VERSION 5.7 ;
  NOWIREEXTENSIONATPIN ON ;
  DIVIDERCHAR "/" ;
  BUSBITCHARS "[]" ;
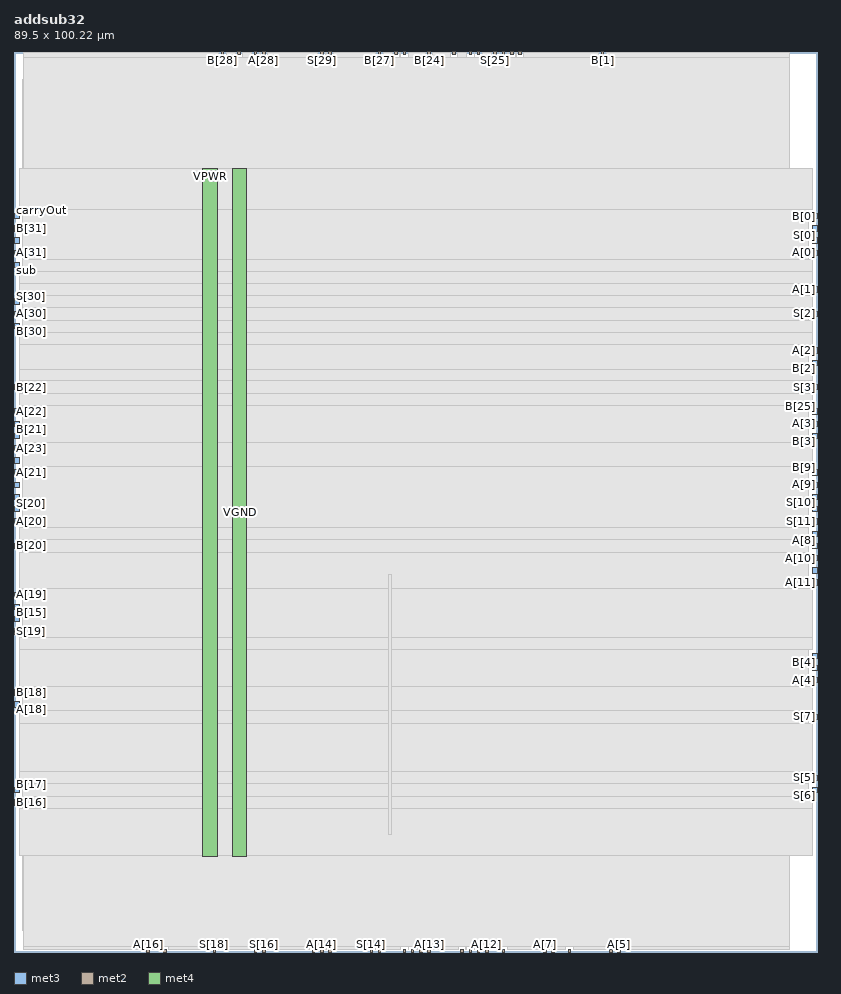
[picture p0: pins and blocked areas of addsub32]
MACRO addsub32
  CLASS BLOCK ;
  FOREIGN addsub32 ;
  ORIGIN 0.000 0.000 ;
  SIZE 89.500 BY 100.220 ;
  PIN A[0]
    DIRECTION INPUT ;
    USE SIGNAL ;
    ANTENNAGATEAREA 0.126000 ;
    PORT
      LAYER met3 ;
        RECT 88.900 77.560 89.500 78.160 ;
    END
  END A[0]
  PIN A[10]
    DIRECTION INPUT ;
    USE SIGNAL ;
    ANTENNAGATEAREA 0.213000 ;
    PORT
      LAYER met3 ;
        RECT 88.900 43.560 89.500 44.160 ;
    END
  END A[10]
  PIN A[11]
    DIRECTION INPUT ;
    USE SIGNAL ;
    ANTENNAGATEAREA 0.213000 ;
    PORT
      LAYER met3 ;
        RECT 88.900 40.840 89.500 41.440 ;
    END
  END A[11]
  PIN A[12]
    DIRECTION INPUT ;
    USE SIGNAL ;
    ANTENNAGATEAREA 0.213000 ;
    PORT
      LAYER met2 ;
        RECT 52.530 0.000 52.810 0.280 ;
    END
  END A[12]
  PIN A[13]
    DIRECTION INPUT ;
    USE SIGNAL ;
    ANTENNAGATEAREA 0.213000 ;
    PORT
      LAYER met2 ;
        RECT 46.090 0.000 46.370 0.280 ;
    END
  END A[13]
  PIN A[14]
    DIRECTION INPUT ;
    USE SIGNAL ;
    ANTENNAGATEAREA 0.213000 ;
    PORT
      LAYER met2 ;
        RECT 34.130 0.000 34.410 0.280 ;
    END
  END A[14]
  PIN A[15]
    DIRECTION INPUT ;
    USE SIGNAL ;
    ANTENNAGATEAREA 0.213000 ;
    PORT
      LAYER met2 ;
        RECT 35.050 0.000 35.330 0.280 ;
    END
  END A[15]
  PIN A[16]
    DIRECTION INPUT ;
    USE SIGNAL ;
    ANTENNAGATEAREA 0.213000 ;
    PORT
      LAYER met2 ;
        RECT 14.810 0.000 15.090 0.280 ;
    END
  END A[16]
  PIN A[17]
    DIRECTION INPUT ;
    USE SIGNAL ;
    ANTENNAGATEAREA 0.213000 ;
    PORT
      LAYER met2 ;
        RECT 16.650 0.000 16.930 0.280 ;
    END
  END A[17]
  PIN A[18]
    DIRECTION INPUT ;
    USE SIGNAL ;
    ANTENNAGATEAREA 0.213000 ;
    PORT
      LAYER met3 ;
        RECT 0.000 27.240 0.600 27.840 ;
    END
  END A[18]
  PIN A[19]
    DIRECTION INPUT ;
    USE SIGNAL ;
    ANTENNAGATEAREA 0.213000 ;
    PORT
      LAYER met3 ;
        RECT 0.000 39.480 0.600 40.080 ;
    END
  END A[19]
  PIN A[1]
    DIRECTION INPUT ;
    USE SIGNAL ;
    ANTENNAGATEAREA 0.126000 ;
    PORT
      LAYER met3 ;
        RECT 88.900 73.480 89.500 74.080 ;
    END
  END A[1]
  PIN A[20]
    DIRECTION INPUT ;
    USE SIGNAL ;
    ANTENNAGATEAREA 0.213000 ;
    PORT
      LAYER met3 ;
        RECT 0.000 47.640 0.600 48.240 ;
    END
  END A[20]
  PIN A[21]
    DIRECTION INPUT ;
    USE SIGNAL ;
    ANTENNAGATEAREA 0.213000 ;
    PORT
      LAYER met3 ;
        RECT 0.000 53.080 0.600 53.680 ;
    END
  END A[21]
  PIN A[22]
    DIRECTION INPUT ;
    USE SIGNAL ;
    ANTENNAGATEAREA 0.213000 ;
    PORT
      LAYER met3 ;
        RECT 0.000 59.880 0.600 60.480 ;
    END
  END A[22]
  PIN A[23]
    DIRECTION INPUT ;
    USE SIGNAL ;
    ANTENNAGATEAREA 0.213000 ;
    PORT
      LAYER met3 ;
        RECT 0.000 55.800 0.600 56.400 ;
    END
  END A[23]
  PIN A[24]
    DIRECTION INPUT ;
    USE SIGNAL ;
    ANTENNAGATEAREA 0.213000 ;
    PORT
      LAYER met2 ;
        RECT 48.850 99.940 49.130 100.220 ;
    END
  END A[24]
  PIN A[25]
    DIRECTION INPUT ;
    USE SIGNAL ;
    ANTENNAGATEAREA 0.213000 ;
    PORT
      LAYER met2 ;
        RECT 51.610 99.940 51.890 100.220 ;
    END
  END A[25]
  PIN A[26]
    DIRECTION INPUT ;
    USE SIGNAL ;
    ANTENNAGATEAREA 0.213000 ;
    PORT
      LAYER met2 ;
        RECT 56.210 99.940 56.490 100.220 ;
    END
  END A[26]
  PIN A[27]
    DIRECTION INPUT ;
    USE SIGNAL ;
    ANTENNAGATEAREA 0.213000 ;
    PORT
      LAYER met2 ;
        RECT 43.330 99.940 43.610 100.220 ;
    END
  END A[27]
  PIN A[28]
    DIRECTION INPUT ;
    USE SIGNAL ;
    ANTENNAGATEAREA 0.213000 ;
    PORT
      LAYER met2 ;
        RECT 27.690 99.940 27.970 100.220 ;
    END
  END A[28]
  PIN A[29]
    DIRECTION INPUT ;
    USE SIGNAL ;
    ANTENNAGATEAREA 0.213000 ;
    PORT
      LAYER met2 ;
        RECT 26.770 99.940 27.050 100.220 ;
    END
  END A[29]
  PIN A[2]
    DIRECTION INPUT ;
    USE SIGNAL ;
    ANTENNAGATEAREA 0.213000 ;
    PORT
      LAYER met3 ;
        RECT 88.900 66.680 89.500 67.280 ;
    END
  END A[2]
  PIN A[30]
    DIRECTION INPUT ;
    USE SIGNAL ;
    ANTENNAGATEAREA 0.213000 ;
    PORT
      LAYER met3 ;
        RECT 0.000 70.760 0.600 71.360 ;
    END
  END A[30]
  PIN A[31]
    DIRECTION INPUT ;
    USE SIGNAL ;
    ANTENNAGATEAREA 0.213000 ;
    PORT
      LAYER met3 ;
        RECT 0.000 77.560 0.600 78.160 ;
    END
  END A[31]
  PIN A[3]
    DIRECTION INPUT ;
    USE SIGNAL ;
    ANTENNAGATEAREA 0.213000 ;
    PORT
      LAYER met3 ;
        RECT 88.900 58.520 89.500 59.120 ;
    END
  END A[3]
  PIN A[4]
    DIRECTION INPUT ;
    USE SIGNAL ;
    ANTENNAGATEAREA 0.213000 ;
    PORT
      LAYER met3 ;
        RECT 88.900 29.960 89.500 30.560 ;
    END
  END A[4]
  PIN A[5]
    DIRECTION INPUT ;
    USE SIGNAL ;
    ANTENNAGATEAREA 0.213000 ;
    PORT
      LAYER met2 ;
        RECT 67.250 0.000 67.530 0.280 ;
    END
  END A[5]
  PIN A[6]
    DIRECTION INPUT ;
    USE SIGNAL ;
    ANTENNAGATEAREA 0.213000 ;
    PORT
      LAYER met2 ;
        RECT 66.330 0.000 66.610 0.280 ;
    END
  END A[6]
  PIN A[7]
    DIRECTION INPUT ;
    USE SIGNAL ;
    ANTENNAGATEAREA 0.213000 ;
    PORT
      LAYER met2 ;
        RECT 58.970 0.000 59.250 0.280 ;
    END
  END A[7]
  PIN A[8]
    DIRECTION INPUT ;
    USE SIGNAL ;
    ANTENNAGATEAREA 0.213000 ;
    PORT
      LAYER met3 ;
        RECT 88.900 44.920 89.500 45.520 ;
    END
  END A[8]
  PIN A[9]
    DIRECTION INPUT ;
    USE SIGNAL ;
    ANTENNAGATEAREA 0.213000 ;
    PORT
      LAYER met3 ;
        RECT 88.900 51.720 89.500 52.320 ;
    END
  END A[9]
  PIN B[0]
    DIRECTION INPUT ;
    USE SIGNAL ;
    ANTENNAGATEAREA 0.213000 ;
    PORT
      LAYER met3 ;
        RECT 88.900 81.640 89.500 82.240 ;
    END
  END B[0]
  PIN B[10]
    DIRECTION INPUT ;
    USE SIGNAL ;
    ANTENNAGATEAREA 0.213000 ;
    PORT
      LAYER met2 ;
        RECT 43.330 0.000 43.610 0.280 ;
    END
  END B[10]
  PIN B[11]
    DIRECTION INPUT ;
    USE SIGNAL ;
    ANTENNAGATEAREA 0.213000 ;
    PORT
      LAYER met2 ;
        RECT 45.170 0.000 45.450 0.280 ;
    END
  END B[11]
  PIN B[12]
    DIRECTION INPUT ;
    USE SIGNAL ;
    ANTENNAGATEAREA 0.213000 ;
    PORT
      LAYER met2 ;
        RECT 49.770 0.000 50.050 0.280 ;
    END
  END B[12]
  PIN B[13]
    DIRECTION INPUT ;
    USE SIGNAL ;
    ANTENNAGATEAREA 0.213000 ;
    PORT
      LAYER met2 ;
        RECT 44.250 0.000 44.530 0.280 ;
    END
  END B[13]
  PIN B[14]
    DIRECTION INPUT ;
    USE SIGNAL ;
    ANTENNAGATEAREA 0.213000 ;
    PORT
      LAYER met2 ;
        RECT 33.210 0.000 33.490 0.280 ;
    END
  END B[14]
  PIN B[15]
    DIRECTION INPUT ;
    USE SIGNAL ;
    ANTENNAGATEAREA 0.213000 ;
    PORT
      LAYER met3 ;
        RECT 0.000 38.120 0.600 38.720 ;
    END
  END B[15]
  PIN B[16]
    DIRECTION INPUT ;
    USE SIGNAL ;
    ANTENNAGATEAREA 0.213000 ;
    PORT
      LAYER met3 ;
        RECT 0.000 16.360 0.600 16.960 ;
    END
  END B[16]
  PIN B[17]
    DIRECTION INPUT ;
    USE SIGNAL ;
    ANTENNAGATEAREA 0.213000 ;
    PORT
      LAYER met3 ;
        RECT 0.000 17.720 0.600 18.320 ;
    END
  END B[17]
  PIN B[18]
    DIRECTION INPUT ;
    USE SIGNAL ;
    ANTENNAGATEAREA 0.213000 ;
    PORT
      LAYER met3 ;
        RECT 0.000 28.600 0.600 29.200 ;
    END
  END B[18]
  PIN B[19]
    DIRECTION INPUT ;
    USE SIGNAL ;
    ANTENNAGATEAREA 0.213000 ;
    PORT
      LAYER met3 ;
        RECT 0.000 36.760 0.600 37.360 ;
    END
  END B[19]
  PIN B[1]
    DIRECTION INPUT ;
    USE SIGNAL ;
    ANTENNAGATEAREA 0.213000 ;
    PORT
      LAYER met2 ;
        RECT 65.410 99.940 65.690 100.220 ;
    END
  END B[1]
  PIN B[20]
    DIRECTION INPUT ;
    USE SIGNAL ;
    ANTENNAGATEAREA 0.213000 ;
    PORT
      LAYER met3 ;
        RECT 0.000 44.920 0.600 45.520 ;
    END
  END B[20]
  PIN B[21]
    DIRECTION INPUT ;
    USE SIGNAL ;
    ANTENNAGATEAREA 0.213000 ;
    PORT
      LAYER met3 ;
        RECT 0.000 58.520 0.600 59.120 ;
    END
  END B[21]
  PIN B[22]
    DIRECTION INPUT ;
    USE SIGNAL ;
    ANTENNAGATEAREA 0.213000 ;
    PORT
      LAYER met3 ;
        RECT 0.000 62.600 0.600 63.200 ;
    END
  END B[22]
  PIN B[23]
    DIRECTION INPUT ;
    USE SIGNAL ;
    ANTENNAGATEAREA 0.213000 ;
    PORT
      LAYER met3 ;
        RECT 0.000 54.440 0.600 55.040 ;
    END
  END B[23]
  PIN B[24]
    DIRECTION INPUT ;
    USE SIGNAL ;
    ANTENNAGATEAREA 0.213000 ;
    PORT
      LAYER met2 ;
        RECT 46.090 99.940 46.370 100.220 ;
    END
  END B[24]
  PIN B[25]
    DIRECTION INPUT ;
    USE SIGNAL ;
    ANTENNAGATEAREA 0.213000 ;
    PORT
      LAYER met3 ;
        RECT 88.900 59.880 89.500 60.480 ;
    END
  END B[25]
  PIN B[26]
    DIRECTION INPUT ;
    USE SIGNAL ;
    ANTENNAGATEAREA 0.213000 ;
    PORT
      LAYER met2 ;
        RECT 55.290 99.940 55.570 100.220 ;
    END
  END B[26]
  PIN B[27]
    DIRECTION INPUT ;
    USE SIGNAL ;
    ANTENNAGATEAREA 0.213000 ;
    PORT
      LAYER met2 ;
        RECT 40.570 99.940 40.850 100.220 ;
    END
  END B[27]
  PIN B[28]
    DIRECTION INPUT ;
    USE SIGNAL ;
    ANTENNAGATEAREA 0.213000 ;
    PORT
      LAYER met2 ;
        RECT 23.090 99.940 23.370 100.220 ;
    END
  END B[28]
  PIN B[29]
    DIRECTION INPUT ;
    USE SIGNAL ;
    ANTENNAGATEAREA 0.213000 ;
    PORT
      LAYER met2 ;
        RECT 24.930 99.940 25.210 100.220 ;
    END
  END B[29]
  PIN B[2]
    DIRECTION INPUT ;
    USE SIGNAL ;
    ANTENNAGATEAREA 0.213000 ;
    PORT
      LAYER met3 ;
        RECT 88.900 65.320 89.500 65.920 ;
    END
  END B[2]
  PIN B[30]
    DIRECTION INPUT ;
    USE SIGNAL ;
    ANTENNAGATEAREA 0.213000 ;
    PORT
      LAYER met3 ;
        RECT 0.000 69.400 0.600 70.000 ;
    END
  END B[30]
  PIN B[31]
    DIRECTION INPUT ;
    USE SIGNAL ;
    ANTENNAGATEAREA 0.213000 ;
    PORT
      LAYER met3 ;
        RECT 0.000 80.280 0.600 80.880 ;
    END
  END B[31]
  PIN B[3]
    DIRECTION INPUT ;
    USE SIGNAL ;
    ANTENNAGATEAREA 0.213000 ;
    PORT
      LAYER met3 ;
        RECT 88.900 57.160 89.500 57.760 ;
    END
  END B[3]
  PIN B[4]
    DIRECTION INPUT ;
    USE SIGNAL ;
    ANTENNAGATEAREA 0.213000 ;
    PORT
      LAYER met3 ;
        RECT 88.900 31.320 89.500 31.920 ;
    END
  END B[4]
  PIN B[5]
    DIRECTION INPUT ;
    USE SIGNAL ;
    ANTENNAGATEAREA 0.213000 ;
    PORT
      LAYER met2 ;
        RECT 61.730 0.000 62.010 0.280 ;
    END
  END B[5]
  PIN B[6]
    DIRECTION INPUT ;
    USE SIGNAL ;
    ANTENNAGATEAREA 0.213000 ;
    PORT
      LAYER met2 ;
        RECT 59.890 0.000 60.170 0.280 ;
    END
  END B[6]
  PIN B[7]
    DIRECTION INPUT ;
    USE SIGNAL ;
    ANTENNAGATEAREA 0.213000 ;
    PORT
      LAYER met2 ;
        RECT 54.370 0.000 54.650 0.280 ;
    END
  END B[7]
  PIN B[8]
    DIRECTION INPUT ;
    USE SIGNAL ;
    ANTENNAGATEAREA 0.213000 ;
    PORT
      LAYER met3 ;
        RECT 88.900 46.280 89.500 46.880 ;
    END
  END B[8]
  PIN B[9]
    DIRECTION INPUT ;
    USE SIGNAL ;
    ANTENNAGATEAREA 0.213000 ;
    PORT
      LAYER met3 ;
        RECT 88.900 53.080 89.500 53.680 ;
    END
  END B[9]
  PIN S[0]
    DIRECTION OUTPUT ;
    USE SIGNAL ;
    ANTENNADIFFAREA 0.702900 ;
    PORT
      LAYER met3 ;
        RECT 88.900 78.920 89.500 79.520 ;
    END
  END S[0]
  PIN S[10]
    DIRECTION OUTPUT ;
    USE SIGNAL ;
    ANTENNADIFFAREA 1.336500 ;
    PORT
      LAYER met3 ;
        RECT 88.900 50.360 89.500 50.960 ;
    END
  END S[10]
  PIN S[11]
    DIRECTION OUTPUT ;
    USE SIGNAL ;
    ANTENNADIFFAREA 1.336500 ;
    PORT
      LAYER met3 ;
        RECT 88.900 47.640 89.500 48.240 ;
    END
  END S[11]
  PIN S[12]
    DIRECTION OUTPUT ;
    USE SIGNAL ;
    ANTENNADIFFAREA 0.795200 ;
    PORT
      LAYER met2 ;
        RECT 51.610 0.000 51.890 0.280 ;
    END
  END S[12]
  PIN S[13]
    DIRECTION OUTPUT ;
    USE SIGNAL ;
    ANTENNADIFFAREA 1.336500 ;
    PORT
      LAYER met2 ;
        RECT 50.690 0.000 50.970 0.280 ;
    END
  END S[13]
  PIN S[14]
    DIRECTION OUTPUT ;
    USE SIGNAL ;
    ANTENNADIFFAREA 1.336500 ;
    PORT
      LAYER met2 ;
        RECT 39.650 0.000 39.930 0.280 ;
    END
  END S[14]
  PIN S[15]
    DIRECTION OUTPUT ;
    USE SIGNAL ;
    ANTENNADIFFAREA 1.336500 ;
    PORT
      LAYER met2 ;
        RECT 40.570 0.000 40.850 0.280 ;
    END
  END S[15]
  PIN S[16]
    DIRECTION OUTPUT ;
    USE SIGNAL ;
    ANTENNADIFFAREA 0.383400 ;
    PORT
      LAYER met2 ;
        RECT 27.690 0.000 27.970 0.280 ;
    END
  END S[16]
  PIN S[17]
    DIRECTION OUTPUT ;
    USE SIGNAL ;
    ANTENNADIFFAREA 1.336500 ;
    PORT
      LAYER met2 ;
        RECT 26.770 0.000 27.050 0.280 ;
    END
  END S[17]
  PIN S[18]
    DIRECTION OUTPUT ;
    USE SIGNAL ;
    ANTENNADIFFAREA 0.795200 ;
    PORT
      LAYER met2 ;
        RECT 22.170 0.000 22.450 0.280 ;
    END
  END S[18]
  PIN S[19]
    DIRECTION OUTPUT ;
    USE SIGNAL ;
    ANTENNADIFFAREA 0.383400 ;
    PORT
      LAYER met3 ;
        RECT 0.000 35.400 0.600 36.000 ;
    END
  END S[19]
  PIN S[1]
    DIRECTION OUTPUT ;
    USE SIGNAL ;
    ANTENNADIFFAREA 1.336500 ;
    PORT
      LAYER met3 ;
        RECT 88.900 80.280 89.500 80.880 ;
    END
  END S[1]
  PIN S[20]
    DIRECTION OUTPUT ;
    USE SIGNAL ;
    ANTENNADIFFAREA 1.336500 ;
    PORT
      LAYER met3 ;
        RECT 0.000 49.000 0.600 49.600 ;
    END
  END S[20]
  PIN S[21]
    DIRECTION OUTPUT ;
    USE SIGNAL ;
    ANTENNADIFFAREA 0.891000 ;
    PORT
      LAYER met3 ;
        RECT 0.000 50.360 0.600 50.960 ;
    END
  END S[21]
  PIN S[22]
    DIRECTION OUTPUT ;
    USE SIGNAL ;
    ANTENNADIFFAREA 0.891000 ;
    PORT
      LAYER met3 ;
        RECT 0.000 57.160 0.600 57.760 ;
    END
  END S[22]
  PIN S[23]
    DIRECTION OUTPUT ;
    USE SIGNAL ;
    ANTENNADIFFAREA 1.336500 ;
    PORT
      LAYER met3 ;
        RECT 0.000 51.720 0.600 52.320 ;
    END
  END S[23]
  PIN S[24]
    DIRECTION OUTPUT ;
    USE SIGNAL ;
    ANTENNADIFFAREA 0.795200 ;
    PORT
      LAYER met2 ;
        RECT 42.410 99.940 42.690 100.220 ;
    END
  END S[24]
  PIN S[25]
    DIRECTION OUTPUT ;
    USE SIGNAL ;
    ANTENNADIFFAREA 1.336500 ;
    PORT
      LAYER met2 ;
        RECT 53.450 99.940 53.730 100.220 ;
    END
  END S[25]
  PIN S[26]
    DIRECTION OUTPUT ;
    USE SIGNAL ;
    ANTENNADIFFAREA 1.336500 ;
    PORT
      LAYER met2 ;
        RECT 54.370 99.940 54.650 100.220 ;
    END
  END S[26]
  PIN S[27]
    DIRECTION OUTPUT ;
    USE SIGNAL ;
    ANTENNADIFFAREA 0.891000 ;
    PORT
      LAYER met2 ;
        RECT 50.690 99.940 50.970 100.220 ;
    END
  END S[27]
  PIN S[28]
    DIRECTION OUTPUT ;
    USE SIGNAL ;
    ANTENNADIFFAREA 0.891000 ;
    PORT
      LAYER met2 ;
        RECT 35.050 99.940 35.330 100.220 ;
    END
  END S[28]
  PIN S[29]
    DIRECTION OUTPUT ;
    USE SIGNAL ;
    ANTENNADIFFAREA 1.336500 ;
    PORT
      LAYER met2 ;
        RECT 34.130 99.940 34.410 100.220 ;
    END
  END S[29]
  PIN S[2]
    DIRECTION OUTPUT ;
    USE SIGNAL ;
    ANTENNADIFFAREA 1.336500 ;
    PORT
      LAYER met3 ;
        RECT 88.900 70.760 89.500 71.360 ;
    END
  END S[2]
  PIN S[30]
    DIRECTION OUTPUT ;
    USE SIGNAL ;
    ANTENNADIFFAREA 0.891000 ;
    PORT
      LAYER met3 ;
        RECT 0.000 72.120 0.600 72.720 ;
    END
  END S[30]
  PIN S[31]
    DIRECTION OUTPUT ;
    USE SIGNAL ;
    ANTENNADIFFAREA 1.336500 ;
    PORT
      LAYER met3 ;
        RECT 0.000 78.920 0.600 79.520 ;
    END
  END S[31]
  PIN S[3]
    DIRECTION OUTPUT ;
    USE SIGNAL ;
    ANTENNADIFFAREA 1.336500 ;
    PORT
      LAYER met3 ;
        RECT 88.900 62.600 89.500 63.200 ;
    END
  END S[3]
  PIN S[4]
    DIRECTION OUTPUT ;
    USE SIGNAL ;
    ANTENNADIFFAREA 1.336500 ;
    PORT
      LAYER met3 ;
        RECT 88.900 32.680 89.500 33.280 ;
    END
  END S[4]
  PIN S[5]
    DIRECTION OUTPUT ;
    USE SIGNAL ;
    ANTENNADIFFAREA 1.336500 ;
    PORT
      LAYER met3 ;
        RECT 88.900 19.080 89.500 19.680 ;
    END
  END S[5]
  PIN S[6]
    DIRECTION OUTPUT ;
    USE SIGNAL ;
    ANTENNADIFFAREA 1.336500 ;
    PORT
      LAYER met3 ;
        RECT 88.900 17.720 89.500 18.320 ;
    END
  END S[6]
  PIN S[7]
    DIRECTION OUTPUT ;
    USE SIGNAL ;
    ANTENNADIFFAREA 1.336500 ;
    PORT
      LAYER met3 ;
        RECT 88.900 25.880 89.500 26.480 ;
    END
  END S[7]
  PIN S[8]
    DIRECTION OUTPUT ;
    USE SIGNAL ;
    ANTENNADIFFAREA 1.336500 ;
    PORT
      LAYER met3 ;
        RECT 88.900 42.200 89.500 42.800 ;
    END
  END S[8]
  PIN S[9]
    DIRECTION OUTPUT ;
    USE SIGNAL ;
    ANTENNADIFFAREA 1.336500 ;
    PORT
      LAYER met3 ;
        RECT 88.900 49.000 89.500 49.600 ;
    END
  END S[9]
  PIN VGND
    DIRECTION INOUT ;
    USE GROUND ;
    PORT
      LAYER met4 ;
        RECT 24.340 10.640 25.940 87.280 ;
    END
  END VGND
  PIN VPWR
    DIRECTION INOUT ;
    USE POWER ;
    PORT
      LAYER met4 ;
        RECT 21.040 10.640 22.640 87.280 ;
    END
  END VPWR
  PIN carryOut
    DIRECTION OUTPUT ;
    USE SIGNAL ;
    ANTENNADIFFAREA 1.336500 ;
    PORT
      LAYER met3 ;
        RECT 0.000 81.640 0.600 82.240 ;
    END
  END carryOut
  PIN sub
    DIRECTION INPUT ;
    USE SIGNAL ;
    ANTENNAGATEAREA 0.990000 ;
    PORT
      LAYER met3 ;
        RECT 0.000 76.200 0.600 76.800 ;
    END
  END sub
  OBS
      LAYER nwell ;
        RECT 5.330 10.795 83.910 87.125 ;
      LAYER li1 ;
        RECT 5.520 10.795 83.720 87.125 ;
      LAYER met1 ;
        RECT 0.990 2.420 86.410 97.200 ;
      LAYER met2 ;
        RECT 1.010 99.660 22.810 100.150 ;
        RECT 23.650 99.660 24.650 100.150 ;
        RECT 25.490 99.660 26.490 100.150 ;
        RECT 27.330 99.660 27.410 100.150 ;
        RECT 28.250 99.660 33.850 100.150 ;
        RECT 34.690 99.660 34.770 100.150 ;
        RECT 35.610 99.660 40.290 100.150 ;
        RECT 41.130 99.660 42.130 100.150 ;
        RECT 42.970 99.660 43.050 100.150 ;
        RECT 43.890 99.660 45.810 100.150 ;
        RECT 46.650 99.660 48.570 100.150 ;
        RECT 49.410 99.660 50.410 100.150 ;
        RECT 51.250 99.660 51.330 100.150 ;
        RECT 52.170 99.660 53.170 100.150 ;
        RECT 54.010 99.660 54.090 100.150 ;
        RECT 54.930 99.660 55.010 100.150 ;
        RECT 55.850 99.660 55.930 100.150 ;
        RECT 56.770 99.660 65.130 100.150 ;
        RECT 65.970 99.660 86.390 100.150 ;
        RECT 1.010 0.560 86.390 99.660 ;
        RECT 1.010 0.280 14.530 0.560 ;
        RECT 15.370 0.280 16.370 0.560 ;
        RECT 17.210 0.280 21.890 0.560 ;
        RECT 22.730 0.280 26.490 0.560 ;
        RECT 27.330 0.280 27.410 0.560 ;
        RECT 28.250 0.280 32.930 0.560 ;
        RECT 33.770 0.280 33.850 0.560 ;
        RECT 34.690 0.280 34.770 0.560 ;
        RECT 35.610 0.280 39.370 0.560 ;
        RECT 40.210 0.280 40.290 0.560 ;
        RECT 41.130 0.280 43.050 0.560 ;
        RECT 43.890 0.280 43.970 0.560 ;
        RECT 44.810 0.280 44.890 0.560 ;
        RECT 45.730 0.280 45.810 0.560 ;
        RECT 46.650 0.280 49.490 0.560 ;
        RECT 50.330 0.280 50.410 0.560 ;
        RECT 51.250 0.280 51.330 0.560 ;
        RECT 52.170 0.280 52.250 0.560 ;
        RECT 53.090 0.280 54.090 0.560 ;
        RECT 54.930 0.280 58.690 0.560 ;
        RECT 59.530 0.280 59.610 0.560 ;
        RECT 60.450 0.280 61.450 0.560 ;
        RECT 62.290 0.280 66.050 0.560 ;
        RECT 66.890 0.280 66.970 0.560 ;
        RECT 67.810 0.280 86.390 0.560 ;
      LAYER met3 ;
        RECT 0.600 82.640 88.900 87.205 ;
        RECT 1.000 77.160 88.500 82.640 ;
        RECT 1.000 75.800 88.900 77.160 ;
        RECT 0.600 74.480 88.900 75.800 ;
        RECT 0.600 73.120 88.500 74.480 ;
        RECT 1.000 73.080 88.500 73.120 ;
        RECT 1.000 71.760 88.900 73.080 ;
        RECT 1.000 70.360 88.500 71.760 ;
        RECT 1.000 69.000 88.900 70.360 ;
        RECT 0.600 67.680 88.900 69.000 ;
        RECT 0.600 64.920 88.500 67.680 ;
        RECT 0.600 63.600 88.900 64.920 ;
        RECT 1.000 62.200 88.500 63.600 ;
        RECT 0.600 60.880 88.900 62.200 ;
        RECT 1.000 56.760 88.500 60.880 ;
        RECT 1.000 54.080 88.900 56.760 ;
        RECT 1.000 47.240 88.500 54.080 ;
        RECT 0.600 45.920 88.500 47.240 ;
        RECT 1.000 44.520 88.500 45.920 ;
        RECT 0.600 40.480 88.500 44.520 ;
        RECT 1.000 40.440 88.500 40.480 ;
        RECT 1.000 35.000 88.900 40.440 ;
        RECT 0.600 33.680 88.900 35.000 ;
        RECT 0.600 29.600 88.500 33.680 ;
        RECT 1.000 29.560 88.500 29.600 ;
        RECT 1.000 26.880 88.900 29.560 ;
        RECT 1.000 26.840 88.500 26.880 ;
        RECT 0.600 25.480 88.500 26.840 ;
        RECT 0.600 20.080 88.900 25.480 ;
        RECT 0.600 18.720 88.500 20.080 ;
        RECT 1.000 17.320 88.500 18.720 ;
        RECT 1.000 15.960 88.900 17.320 ;
        RECT 0.600 10.715 88.900 15.960 ;
      LAYER met4 ;
        RECT 41.695 13.095 42.025 41.985 ;
  END
END addsub32
END LIBRARY

